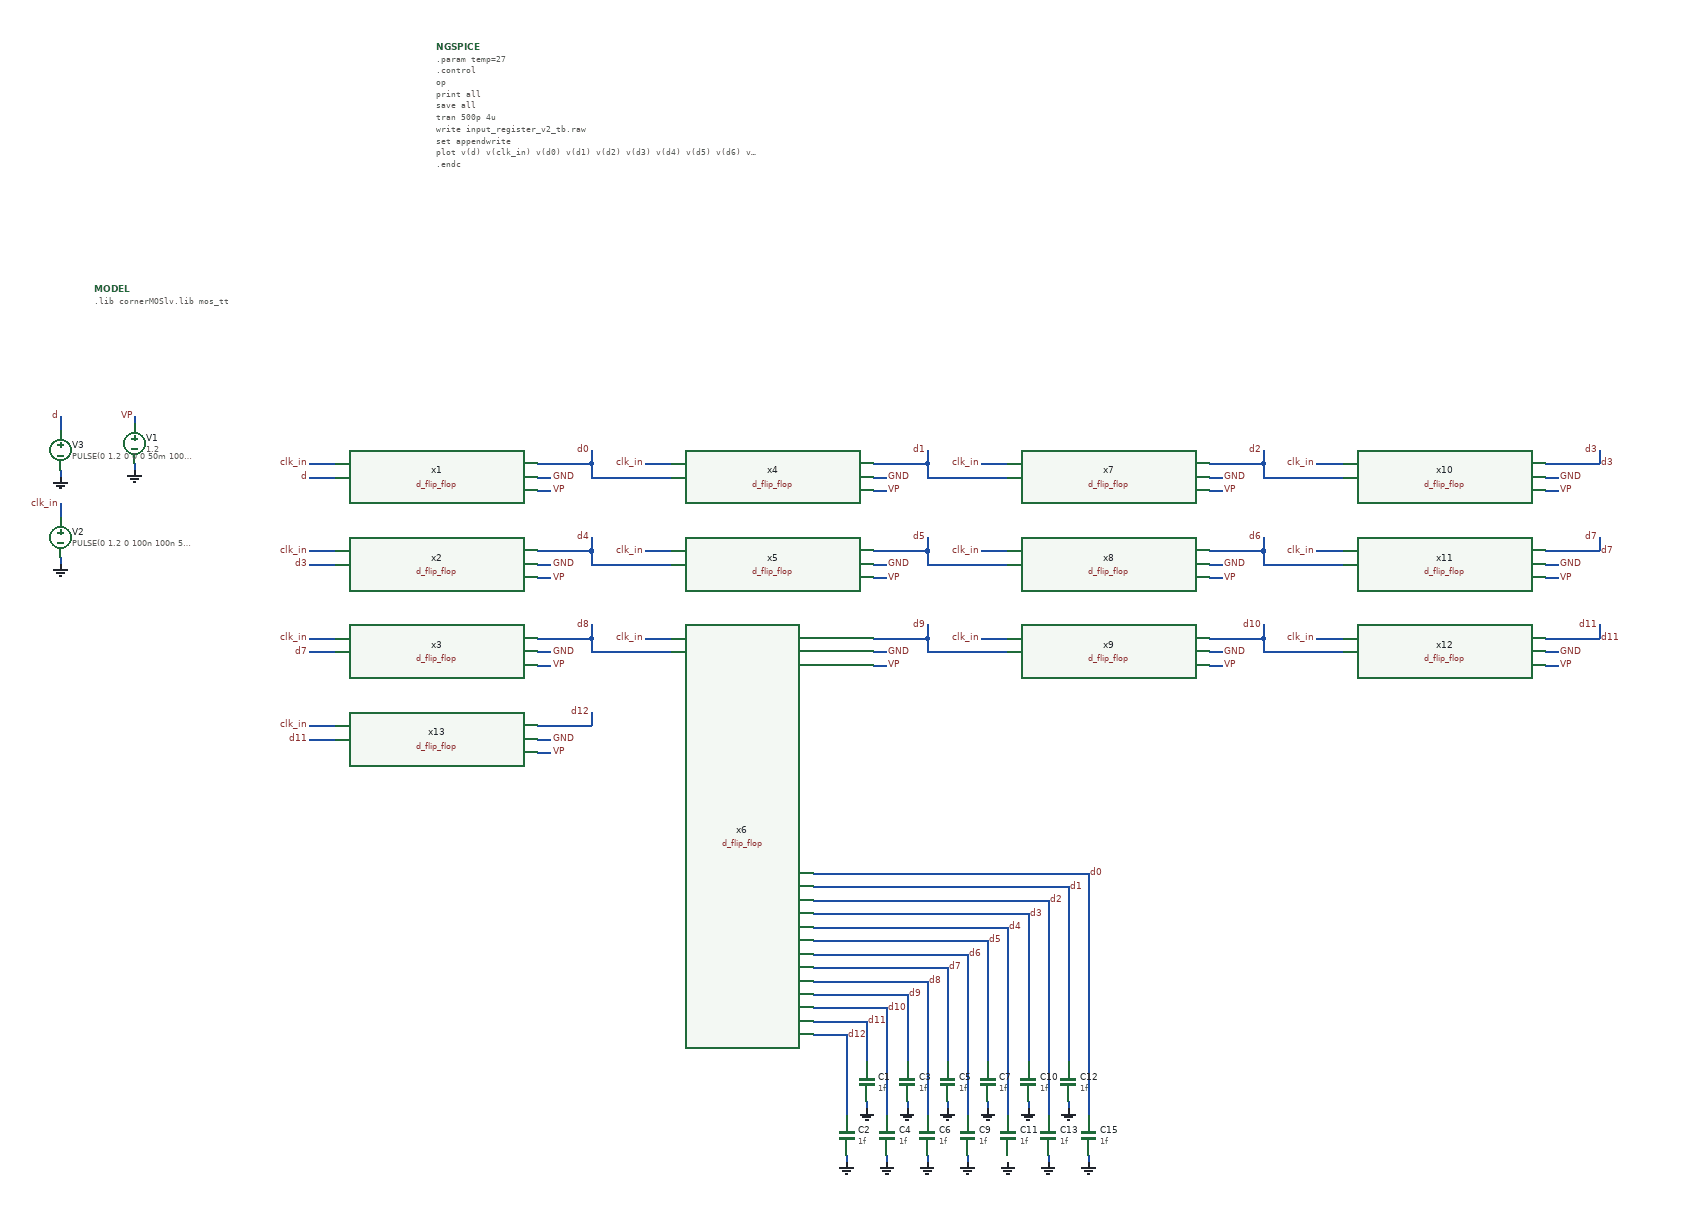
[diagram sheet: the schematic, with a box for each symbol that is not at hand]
v {xschem version=3.4.8RC file_version=1.3}
G {}
K {}
V {}
S {}
F {}
E {}
N -210 -40 -190 -40 {lab=GND}
N -210 -20 -190 -20 {lab=VP}
N -550 -60 -510 -60 {lab=clk_in}
N -550 -40 -510 -40 {lab=d}
N -50 -60 -10 -60 {lab=clk_in}
N -210 -60 -130 -60 {lab=d0}
N -130 -60 -130 -40 {lab=d0}
N -130 -40 -10 -40 {lab=d0}
N -130 -80 -130 -60 {lab=d0}
N 290 -40 310 -40 {lab=GND}
N 290 -20 310 -20 {lab=VP}
N 450 -60 490 -60 {lab=clk_in}
N 290 -60 370 -60 {lab=d1}
N 370 -60 370 -40 {lab=d1}
N 370 -40 490 -40 {lab=d1}
N 370 -80 370 -60 {lab=d1}
N 790 -40 810 -40 {lab=GND}
N 790 -20 810 -20 {lab=VP}
N 950 -60 990 -60 {lab=clk_in}
N 790 -60 870 -60 {lab=d2}
N 870 -60 870 -40 {lab=d2}
N 870 -40 990 -40 {lab=d2}
N 870 -80 870 -60 {lab=d2}
N 1290 -40 1310 -40 {lab=GND}
N 1290 -20 1310 -20 {lab=VP}
N 1290 -60 1370 -60 {lab=d3}
N 1370 -80 1370 -60 {lab=d3}
N -210 90 -190 90 {lab=GND}
N -210 110 -190 110 {lab=VP}
N -550 70 -510 70 {lab=clk_in}
N -550 90 -510 90 {lab=d3}
N -50 70 -10 70 {lab=clk_in}
N -210 70 -130 70 {lab=d4}
N -130 70 -130 90 {lab=d4}
N -130 90 -10 90 {lab=d4}
N -130 50 -130 70 {lab=d4}
N 290 90 310 90 {lab=GND}
N 290 110 310 110 {lab=VP}
N 450 70 490 70 {lab=clk_in}
N 290 70 370 70 {lab=d5}
N 370 70 370 90 {lab=d5}
N 370 90 490 90 {lab=d5}
N 370 50 370 70 {lab=d5}
N 790 90 810 90 {lab=GND}
N 790 110 810 110 {lab=VP}
N 950 70 990 70 {lab=clk_in}
N 790 70 870 70 {lab=d6}
N 870 70 870 90 {lab=d6}
N 870 90 990 90 {lab=d6}
N 870 50 870 70 {lab=d6}
N 1290 90 1310 90 {lab=GND}
N 1290 110 1310 110 {lab=VP}
N 1290 70 1370 70 {lab=d7}
N 1370 50 1370 70 {lab=d7}
N -210 220 -190 220 {lab=GND}
N -210 240 -190 240 {lab=VP}
N -550 200 -510 200 {lab=clk_in}
N -550 220 -510 220 {lab=d7}
N -50 200 -10 200 {lab=clk_in}
N -210 200 -130 200 {lab=d8}
N -130 200 -130 220 {lab=d8}
N -130 220 -10 220 {lab=d8}
N -130 180 -130 200 {lab=d8}
N 290 220 310 220 {lab=GND}
N 290 240 310 240 {lab=VP}
N 450 200 490 200 {lab=clk_in}
N 290 200 370 200 {lab=d9}
N 370 200 370 220 {lab=d9}
N 370 220 490 220 {lab=d9}
N 370 180 370 200 {lab=d9}
N 790 220 810 220 {lab=GND}
N 790 240 810 240 {lab=VP}
N 950 200 990 200 {lab=clk_in}
N 790 200 870 200 {lab=d10}
N 870 200 870 220 {lab=d10}
N 870 220 990 220 {lab=d10}
N 870 180 870 200 {lab=d10}
N 1290 220 1310 220 {lab=GND}
N 1290 240 1310 240 {lab=VP}
N 1290 200 1370 200 {lab=d11}
N 1370 180 1370 200 {lab=d11}
N -210 350 -190 350 {lab=GND}
N -210 370 -190 370 {lab=VP}
N -550 330 -510 330 {lab=clk_in}
N -550 350 -510 350 {lab=d11}
N -210 330 -130 330 {lab=d12}
N -130 310 -130 330 {lab=d12}
N -920 0 -920 20 {lab=clk_in}
N -810 -130 -810 -120 {lab=VP}
N -810 -60 -810 -50 {lab=0}
N -920 80 -920 90 {lab=0}
N -920 -130 -920 -110 {lab=d}
N -920 -50 -920 -40 {lab=0}
N 200 770 280 770 {lab=d11}
N 200 730 340 730 {lab=d9}
N 200 690 400 690 {lab=d7}
N 200 650 460 650 {lab=d5}
N 200 610 520 610 {lab=d3}
N 280 890 280 900 {lab=0}
N 250 970 250 980 {lab=0}
N 340 890 340 900 {lab=0}
N 310 970 310 980 {lab=0}
N 400 890 400 900 {lab=0}
N 370 970 370 980 {lab=0}
N 460 890 460 900 {lab=0}
N 430 970 430 980 {lab=0}
N 520 890 520 900 {lab=0}
N 580 890 580 900 {lab=0}
N 550 970 550 980 {lab=0}
N 610 970 610 980 {lab=0}
N 200 790 250 790 {lab=d12}
N 250 790 250 910 {lab=d12}
N 280 770 280 830 {lab=d11}
N 200 750 310 750 {lab=d10}
N 310 750 310 910 {lab=d10}
N 340 730 340 830 {lab=d9}
N 370 710 370 910 {lab=d8}
N 200 710 370 710 {lab=d8}
N 400 690 400 830 {lab=d7}
N 200 670 430 670 {lab=d6}
N 430 670 430 910 {lab=d6}
N 460 650 460 830 {lab=d5}
N 200 630 490 630 {lab=d4}
N 490 630 490 910 {lab=d4}
N 520 610 520 830 {lab=d3}
N 200 590 550 590 {lab=d2}
N 550 590 550 910 {lab=d2}
N 580 570 580 830 {lab=d1}
N 200 570 580 570 {lab=d1}
N 200 550 610 550 {lab=d0}
N 610 550 610 910 {lab=d0}
C {lab_pin.sym} -130 -80 3 0 {name=p3 lab=d0}
C {lab_pin.sym} 370 -80 3 0 {name=p7 lab=d1}
C {lab_pin.sym} 870 -80 3 0 {name=p12 lab=d2
}
C {lab_pin.sym} 1370 -80 3 0 {name=p16 lab=d3
}
C {lab_pin.sym} -130 50 3 0 {name=p20 lab=d4}
C {lab_pin.sym} 370 50 3 0 {name=p25 lab=d5}
C {lab_pin.sym} 870 50 3 0 {name=p29 lab=d6
}
C {lab_pin.sym} 1370 50 3 0 {name=p33 lab=d7
}
C {lab_pin.sym} -130 180 3 0 {name=p36 lab=d8}
C {lab_pin.sym} 370 180 3 0 {name=p41 lab=d9}
C {lab_pin.sym} 870 180 3 0 {name=p45 lab=d10
}
C {lab_pin.sym} 1370 180 3 0 {name=p49 lab=d11
}
C {lab_pin.sym} -130 310 3 0 {name=p53 lab=d12}
C {lab_pin.sym} -190 -40 2 0 {name=p60 sig_type=std_logic lab=GND}
C {lab_pin.sym} -190 -20 2 0 {name=p61 sig_type=std_logic lab=VP}
C {lab_pin.sym} -190 90 2 0 {name=p6 sig_type=std_logic lab=GND}
C {lab_pin.sym} -190 110 2 0 {name=p9 sig_type=std_logic lab=VP}
C {lab_pin.sym} -190 220 2 0 {name=p11 sig_type=std_logic lab=GND}
C {lab_pin.sym} -190 240 2 0 {name=p13 sig_type=std_logic lab=VP}
C {lab_pin.sym} -190 350 2 0 {name=p15 sig_type=std_logic lab=GND}
C {lab_pin.sym} -190 370 2 0 {name=p17 sig_type=std_logic lab=VP}
C {lab_pin.sym} 310 -40 2 0 {name=p19 sig_type=std_logic lab=GND}
C {lab_pin.sym} 310 -20 2 0 {name=p22 sig_type=std_logic lab=VP}
C {lab_pin.sym} 310 90 2 0 {name=p24 sig_type=std_logic lab=GND}
C {lab_pin.sym} 310 110 2 0 {name=p26 sig_type=std_logic lab=VP}
C {lab_pin.sym} 310 220 2 0 {name=p28 sig_type=std_logic lab=GND}
C {lab_pin.sym} 310 240 2 0 {name=p30 sig_type=std_logic lab=VP}
C {lab_pin.sym} 810 -40 2 0 {name=p35 sig_type=std_logic lab=GND}
C {lab_pin.sym} 810 -20 2 0 {name=p38 sig_type=std_logic lab=VP}
C {lab_pin.sym} 810 90 2 0 {name=p40 sig_type=std_logic lab=GND}
C {lab_pin.sym} 810 110 2 0 {name=p42 sig_type=std_logic lab=VP}
C {lab_pin.sym} 810 220 2 0 {name=p44 sig_type=std_logic lab=GND}
C {lab_pin.sym} 810 240 2 0 {name=p46 sig_type=std_logic lab=VP}
C {lab_pin.sym} 1310 -40 2 0 {name=p52 sig_type=std_logic lab=GND}
C {lab_pin.sym} 1310 -20 2 0 {name=p55 sig_type=std_logic lab=VP}
C {lab_pin.sym} 1310 90 2 0 {name=p57 sig_type=std_logic lab=GND}
C {lab_pin.sym} 1310 110 2 0 {name=p59 sig_type=std_logic lab=VP}
C {lab_pin.sym} 1310 220 2 0 {name=p62 sig_type=std_logic lab=GND}
C {lab_pin.sym} 1310 240 2 0 {name=p63 sig_type=std_logic lab=VP}
C {lab_pin.sym} -550 -60 0 0 {name=p8 sig_type=std_logic lab=clk_in}
C {lab_pin.sym} -550 70 0 0 {name=p23 sig_type=std_logic lab=clk_in}
C {lab_pin.sym} -550 200 0 0 {name=p27 sig_type=std_logic lab=clk_in}
C {lab_pin.sym} -550 330 0 0 {name=p31 sig_type=std_logic lab=clk_in}
C {lab_pin.sym} -50 -60 0 0 {name=p37 sig_type=std_logic lab=clk_in}
C {lab_pin.sym} -50 70 0 0 {name=p39 sig_type=std_logic lab=clk_in}
C {lab_pin.sym} -50 200 0 0 {name=p43 sig_type=std_logic lab=clk_in}
C {lab_pin.sym} 450 -60 0 0 {name=p48 sig_type=std_logic lab=clk_in}
C {lab_pin.sym} 450 70 0 0 {name=p50 sig_type=std_logic lab=clk_in}
C {lab_pin.sym} 450 200 0 0 {name=p54 sig_type=std_logic lab=clk_in}
C {lab_pin.sym} 950 -60 0 0 {name=p56 sig_type=std_logic lab=clk_in}
C {lab_pin.sym} 950 70 0 0 {name=p64 sig_type=std_logic lab=clk_in}
C {lab_pin.sym} 950 200 0 0 {name=p65 sig_type=std_logic lab=clk_in}
C {lab_pin.sym} 1370 -60 2 0 {name=p66 sig_type=std_logic lab=d3}
C {lab_pin.sym} 1370 70 2 0 {name=p67 sig_type=std_logic lab=d7}
C {lab_pin.sym} 1370 200 2 0 {name=p69 sig_type=std_logic lab=d11}
C {lab_pin.sym} -550 90 0 0 {name=p70 sig_type=std_logic lab=d3}
C {lab_pin.sym} -550 220 0 0 {name=p71 sig_type=std_logic lab=d7}
C {lab_pin.sym} -550 350 0 0 {name=p72 sig_type=std_logic lab=d11}
C {vsource.sym} -810 -90 0 0 {name=V1 value=1.2 savecurrent=false}
C {vsource.sym} -920 50 0 0 {name=V2 value="PULSE(0 1.2 0 100n 100n 500n 1u)" savecurrent=false}
C {lab_wire.sym} -920 0 0 0 {name=p18 sig_type=std_logic lab=clk_in}
C {lab_wire.sym} -810 -130 0 0 {name=p32 sig_type=std_logic lab=VP
}
C {lab_wire.sym} -920 -130 0 0 {name=p34 sig_type=std_logic lab=d
}
C {vsource.sym} -920 -80 0 0 {name=V3 value="PULSE(0 1.2 0 0 0 50m 100m)" savecurrent=false}
C {gnd.sym} -920 -40 0 0 {name=l2 lab=0
}
C {gnd.sym} -920 90 0 0 {name=l3 lab=0
}
C {gnd.sym} -810 -50 0 0 {name=l4 lab=0
}
C {devices/code_shown.sym} -360 -680 0 0 {name=NGSPICE only_toplevel=false
value="
.param temp=27
.control

op
print all
save all

tran 500p 4u
write input_register_v2_tb.raw
set appendwrite

plot v(d) v(clk_in) v(d0)  v(d1)  v(d2)  v(d3) v(d4) v(d5) v(d6) v(d7) v(d8) v(d9) v(d10) v(d11) v(d12)



.endc
"}
C {lab_wire.sym} 610 550 2 0 {name=p51 sig_type=std_logic lab=d0
}
C {capa.sym} 280 860 2 0 {name=C1
m=1
value=1f
footprint=1206
device="ceramic capacitor"}
C {gnd.sym} 280 900 0 0 {name=l1 lab=0
}
C {capa.sym} 250 940 2 0 {name=C2
m=1
value=1f
footprint=1206
device="ceramic capacitor"}
C {gnd.sym} 250 980 0 0 {name=l6 lab=0
}
C {capa.sym} 340 860 2 0 {name=C3
m=1
value=1f
footprint=1206
device="ceramic capacitor"}
C {gnd.sym} 340 900 0 0 {name=l7 lab=0
}
C {capa.sym} 310 940 2 0 {name=C4
m=1
value=1f
footprint=1206
device="ceramic capacitor"}
C {gnd.sym} 310 980 0 0 {name=l8 lab=0
}
C {capa.sym} 400 860 2 0 {name=C5
m=1
value=1f
footprint=1206
device="ceramic capacitor"}
C {gnd.sym} 400 900 0 0 {name=l9 lab=0
}
C {capa.sym} 370 940 2 0 {name=C6
m=1
value=1f
footprint=1206
device="ceramic capacitor"}
C {gnd.sym} 370 980 0 0 {name=l10 lab=0
}
C {capa.sym} 460 860 2 0 {name=C7
m=1
value=1f
footprint=1206
device="ceramic capacitor"}
C {gnd.sym} 460 900 0 0 {name=l11 lab=0
}
C {capa.sym} 430 940 2 0 {name=C9
m=1
value=1f
footprint=1206
device="ceramic capacitor"}
C {gnd.sym} 430 980 0 0 {name=l13 lab=0
}
C {capa.sym} 520 860 2 0 {name=C10
m=1
value=1f
footprint=1206
device="ceramic capacitor"}
C {gnd.sym} 520 900 0 0 {name=l14 lab=0
}
C {capa.sym} 490 940 2 0 {name=C11
m=1
value=1f
footprint=1206
device="ceramic capacitor"}
C {gnd.sym} 490 980 0 0 {name=l15 lab=0
}
C {capa.sym} 580 860 2 0 {name=C12
m=1
value=1f
footprint=1206
device="ceramic capacitor"}
C {gnd.sym} 580 900 0 0 {name=l16 lab=0
}
C {capa.sym} 550 940 2 0 {name=C13
m=1
value=1f
footprint=1206
device="ceramic capacitor"}
C {gnd.sym} 550 980 0 0 {name=l17 lab=0
}
C {capa.sym} 610 940 2 0 {name=C15
m=1
value=1f
footprint=1206
device="ceramic capacitor"}
C {gnd.sym} 610 980 0 0 {name=l19 lab=0
}
C {lab_wire.sym} 580 570 2 0 {name=p58 sig_type=std_logic lab=d1
}
C {lab_wire.sym} 550 590 2 0 {name=p68 sig_type=std_logic lab=d2
}
C {lab_wire.sym} 520 610 2 0 {name=p73 sig_type=std_logic lab=d3
}
C {lab_wire.sym} 490 630 2 0 {name=p74 sig_type=std_logic lab=d4
}
C {lab_wire.sym} 460 650 2 0 {name=p75 sig_type=std_logic lab=d5
}
C {lab_wire.sym} 430 670 2 0 {name=p76 sig_type=std_logic lab=d6
}
C {lab_wire.sym} 400 690 2 0 {name=p77 sig_type=std_logic lab=d7
}
C {lab_wire.sym} 370 710 2 0 {name=p78 sig_type=std_logic lab=d8
}
C {lab_wire.sym} 340 730 2 0 {name=p79 sig_type=std_logic lab=d9
}
C {lab_wire.sym} 310 750 2 0 {name=p80 sig_type=std_logic lab=d10
}
C {lab_wire.sym} 280 770 2 0 {name=p81 sig_type=std_logic lab=d11
}
C {lab_wire.sym} 250 790 2 0 {name=p82 sig_type=std_logic lab=d12
}
C {/foss/designs/CHIP-PLL/divider/d_flip_flop.sym} -360 -30 0 0 {name=x1}
C {/foss/designs/CHIP-PLL/divider/d_flip_flop.sym} -360 100 0 0 {name=x2}
C {/foss/designs/CHIP-PLL/divider/d_flip_flop.sym} -360 230 0 0 {name=x3}
C {/foss/designs/CHIP-PLL/divider/d_flip_flop.sym} 140 -30 0 0 {name=x4}
C {/foss/designs/CHIP-PLL/divider/d_flip_flop.sym} 140 100 0 0 {name=x5}
C {/foss/designs/CHIP-PLL/divider/d_flip_flop.sym} 140 230 0 0 {name=x6}
C {/foss/designs/CHIP-PLL/divider/d_flip_flop.sym} 640 -30 0 0 {name=x7}
C {/foss/designs/CHIP-PLL/divider/d_flip_flop.sym} 640 100 0 0 {name=x8}
C {/foss/designs/CHIP-PLL/divider/d_flip_flop.sym} 640 230 0 0 {name=x9}
C {/foss/designs/CHIP-PLL/divider/d_flip_flop.sym} 1140 -30 0 0 {name=x10}
C {/foss/designs/CHIP-PLL/divider/d_flip_flop.sym} 1140 100 0 0 {name=x11}
C {/foss/designs/CHIP-PLL/divider/d_flip_flop.sym} 1140 230 0 0 {name=x12}
C {/foss/designs/CHIP-PLL/divider/d_flip_flop.sym} -360 360 0 0 {name=x13}
C {devices/code_shown.sym} -870 -320 0 0 {name=MODEL only_toplevel=true
format="tcleval( @value )"
value=".lib cornerMOSlv.lib mos_tt
"}
C {lab_wire.sym} -550 -40 0 0 {name=p1 sig_type=std_logic lab=d
}
